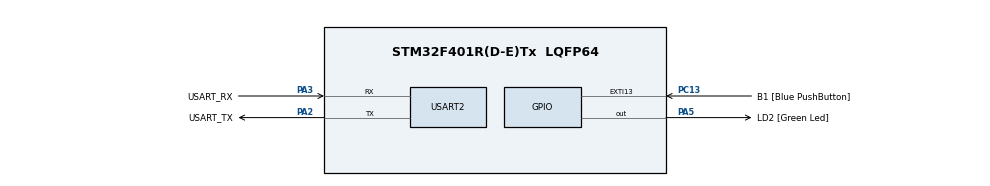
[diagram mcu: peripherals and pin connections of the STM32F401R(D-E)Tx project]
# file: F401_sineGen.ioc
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Mcu.Family=STM32F4
Mcu.Name=STM32F401R(D-E)Tx
Mcu.Package=LQFP64
NVIC.PriorityGroup=NVIC_PRIORITYGROUP_0
PA13.GPIO_Label=TMS
PA13.Mode=Serial_Wire
PA13.Signal=SYS_JTMS-SWDIO
PA14.GPIO_Label=TCK
PA14.Mode=Serial_Wire
PA14.Signal=SYS_JTCK-SWCLK
PA2.GPIO_Label=USART_TX
PA2.GPIO_Mode=GPIO_MODE_AF_PP
PA2.GPIO_PuPd=GPIO_NOPULL
PA2.GPIO_Speed=GPIO_SPEED_FREQ_LOW
PA2.Mode=Asynchronous
PA2.Signal=USART2_TX
PA3.GPIO_Label=USART_RX
PA3.GPIO_Mode=GPIO_MODE_AF_PP
PA3.GPIO_PuPd=GPIO_NOPULL
PA3.GPIO_Speed=GPIO_SPEED_FREQ_LOW
PA3.Mode=Asynchronous
PA3.Signal=USART2_RX
PA5.GPIO_Label=LD2 [Green Led]
PA5.GPIO_Mode=GPIO_MODE_OUTPUT_PP
PA5.GPIO_PuPd=GPIO_NOPULL
PA5.GPIO_Speed=GPIO_SPEED_FREQ_LOW
PA5.Signal=GPIO_Output
PB3.GPIO_Label=SWO
PB3.Signal=SYS_JTDO-SWO
PC13-ANTI_TAMP.GPIO_Label=B1 [Blue PushButton]
PC13-ANTI_TAMP.GPIO_ModeDefaultEXTI=GPIO_MODE_IT_FALLING
PC13-ANTI_TAMP.GPIO_PuPd=GPIO_NOPULL
PC13-ANTI_TAMP.Signal=GPXTI13
PC14-OSC32_IN.Mode=LSE-External-Oscillator
PC14-OSC32_IN.Signal=RCC_OSC32_IN
PC15-OSC32_OUT.Mode=LSE-External-Oscillator
PC15-OSC32_OUT.Signal=RCC_OSC32_OUT
PH0\ -\ OSC_IN.Mode=HSE-External-Clock-Source
PH0\ -\ OSC_IN.Signal=RCC_OSC_IN
PH1\ -\ OSC_OUT.Mode=HSE-External-Clock-Source
PH1\ -\ OSC_OUT.Signal=RCC_OSC_OUT
ProjectManager.HeapSize=0x200
ProjectManager.StackSize=0x400
ProjectManager.TargetToolchain=STM32CubeIDE
RCC.48MHZClocksFreq_Value=24000000
RCC.AHBFreq_Value=84000000
RCC.APB1CLKDivider=RCC_HCLK_DIV2
RCC.APB1Freq_Value=42000000
RCC.APB1TimFreq_Value=84000000
RCC.APB2Freq_Value=84000000
RCC.APB2TimFreq_Value=84000000
RCC.CortexFreq_Value=84000000
RCC.HCLKFreq_Value=84000000
RCC.HSE_VALUE=8000000
RCC.HSI_VALUE=16000000
RCC.PLLM=8
RCC.PLLN=84
RCC.PLLQ=7
RCC.SYSCLKFreq_VALUE=84000000
RCC.SYSCLKSource=RCC_SYSCLKSOURCE_PLLCLK
RCC.VCOOutputFreq_Value=168000000
STMicroelectronics.X-CUBE-AI.9.0.0.ActivationBufferSizeList=128
STMicroelectronics.X-CUBE-AI.9.0.0.ActivationBuffers=pool0
STMicroelectronics.X-CUBE-AI.9.0.0.ActivationNames=pool0
STMicroelectronics.X-CUBE-AI.9.0.0.ActivationSizes=AI_SINE_MODEL_DATA_ACTIVATION_1_SIZE
STMicroelectronics.X-CUBE-AI.9.0.0.HeapSize=0x800
STMicroelectronics.X-CUBE-AI.9.0.0.InternalRamActivationBufferMaxSize=AI_SINE_MODEL_DATA_ACTIVATIONS_SIZE
STMicroelectronics.X-CUBE-AI.9.0.0.LatestDirectoryUsed-be15a7543b8aec642143df37d2f76281d775ac8bf019addfea3917b66998c5c0=/home/stage002/Downloads
STMicroelectronics.X-CUBE-AI.9.0.0.MaximumNumberOfInputLayer=1
STMicroelectronics.X-CUBE-AI.9.0.0.MaximumNumberOfOutputLayer=1
STMicroelectronics.X-CUBE-AI.9.0.0.MaximumSizeOfInputLayer=1
STMicroelectronics.X-CUBE-AI.9.0.0.MaximumSizeOfOutputLayer=1
STMicroelectronics.X-CUBE-AI.9.0.0.ModelActualCompression-be15a7543b8aec642143df37d2f76281d775ac8bf019addfea3917b66998c5c0=0.0
STMicroelectronics.X-CUBE-AI.9.0.0.ModelCompression-be15a7543b8aec642143df37d2f76281d775ac8bf019addfea3917b66998c5c0=None
STMicroelectronics.X-CUBE-AI.9.0.0.ModelFlashOccupation-be15a7543b8aec642143df37d2f76281d775ac8bf019addfea3917b66998c5c0=1284
STMicroelectronics.X-CUBE-AI.9.0.0.ModelHashList=be15a7543b8aec642143df37d2f76281d775ac8bf019addfea3917b66998c5c0
STMicroelectronics.X-CUBE-AI.9.0.0.ModelKind-be15a7543b8aec642143df37d2f76281d775ac8bf019addfea3917b66998c5c0=TFLITE
STMicroelectronics.X-CUBE-AI.9.0.0.ModelMacc-be15a7543b8aec642143df37d2f76281d775ac8bf019addfea3917b66998c5c0=353
STMicroelectronics.X-CUBE-AI.9.0.0.ModelName-be15a7543b8aec642143df37d2f76281d775ac8bf019addfea3917b66998c5c0=sine_model
STMicroelectronics.X-CUBE-AI.9.0.0.ModelNameList=sine_model
STMicroelectronics.X-CUBE-AI.9.0.0.ModelRamOccupation-be15a7543b8aec642143df37d2f76281d775ac8bf019addfea3917b66998c5c0=128
STMicroelectronics.X-CUBE-AI.9.0.0.ModelStructureFile-be15a7543b8aec642143df37d2f76281d775ac8bf019addfea3917b66998c5c0=/home/stage002/Downloads/sine_model.tflite
STMicroelectronics.X-CUBE-AI.9.0.0.ModelType-be15a7543b8aec642143df37d2f76281d775ac8bf019addfea3917b66998c5c0=STM32Cube.AI MCU runtime
STMicroelectronics.X-CUBE-AI.9.0.0.ReadyForCodeGeneration=true
STMicroelectronics.X-CUBE-AI.9.0.0.StackSize=0x800
STMicroelectronics.X-CUBE-AI.9.0.0.WorkingBufferStartAddrList=0xFFFFFFFF
STMicroelectronics.X-CUBE-AI.9.0.0.XAaCUBEAaAICcArtificialOoIntelligenceJjCore=true
STMicroelectronics.X-CUBE-AI.9.0.0.copyWeightToRam-be15a7543b8aec642143df37d2f76281d775ac8bf019addfea3917b66998c5c0=false
STMicroelectronics.X-CUBE-AI.9.0.0.customLayerConfigEnabled-be15a7543b8aec642143df37d2f76281d775ac8bf019addfea3917b66998c5c0=false
STMicroelectronics.X-CUBE-AI.9.0.0.noOnnxIoTranspose-be15a7543b8aec642143df37d2f76281d775ac8bf019addfea3917b66998c5c0=false
STMicroelectronics.X-CUBE-AI.9.0.0.outputDirectory-be15a7543b8aec642143df37d2f76281d775ac8bf019addfea3917b66998c5c0=/home/stage002/.stm32cubemx/sine_model_output
STMicroelectronics.X-CUBE-AI.9.0.0.useInputAllocation-be15a7543b8aec642143df37d2f76281d775ac8bf019addfea3917b66998c5c0=true
STMicroelectronics.X-CUBE-AI.9.0.0.useOutputAllocation-be15a7543b8aec642143df37d2f76281d775ac8bf019addfea3917b66998c5c0=true
TIM10.Prescaler=80-1
USART2.VirtualMode=VM_ASYNC
VP_CRC_VS_CRC.Mode=CRC_Activate
VP_STMicroelectronics.X-CUBE-AI_VS_ArtificialOoIntelligenceJjXAaCUBEAaAI_9.0.0.Mode=ArtificialOoIntelligenceJjXAaCUBEAaAI
VP_TIM10_VS_ClockSourceINT.Mode=Enable_Timer
board=NUCLEO-F401RE

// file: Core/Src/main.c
/* USER CODE BEGIN Header */
/**
  ******************************************************************************
  * @file           : main.c
  * @brief          : Main program body
  ******************************************************************************
  * @attention
  *
  * Copyright (c) 2024 STMicroelectronics.
  * All rights reserved.
  *
  * This software is licensed under terms that can be found in the LICENSE file
  * in the root directory of this software component.
  * If no LICENSE file comes with this software, it is provided AS-IS.
  *
  ******************************************************************************
  */
/* USER CODE END Header */
#include "main.h"
#include <stdio.h>
#include "ai_datatypes_defines.h"
#include "ai_platform.h"
#include "sine_model.h"
#include "sine_model_data.h"

CRC_HandleTypeDef hcrc;

TIM_HandleTypeDef htim10;

UART_HandleTypeDef huart2;

static ai_buffer *ai_input;
static ai_buffer *ai_output;
char buf[50];
int buf_len = 0;
ai_error ai_err;
ai_i32 nbatch;
uint32_t timestamp;
float y_val;
ai_float input = 0;
ai_float a;

/* USER CODE BEGIN PFP */
void SystemClock_Config(void);
static void MX_GPIO_Init(void);
static void MX_USART2_UART_Init(void);
static void MX_TIM10_Init(void);
static void MX_CRC_Init(void);
/* USER CODE END PFP */

/* USER CODE BEGIN 0 */
// Chunk of memory used to hold intermediate values for neural network
  AI_ALIGNED(8) ai_u8 activations[AI_SINE_MODEL_DATA_ACTIVATIONS_SIZE];

  // Buffers used to store input and output tensors
  AI_ALIGNED(8) ai_i8 in_data[AI_SINE_MODEL_IN_1_SIZE_BYTES];
  AI_ALIGNED(8) ai_i8 out_data[AI_SINE_MODEL_OUT_1_SIZE_BYTES];
  // Pointer to our model
  ai_handle sine_model = AI_HANDLE_NULL;

/* USER CODE END 0 */
int aiInit(void) {

	/* Create and initialize the c-model */
	const ai_handle acts[] = {activations};

	ai_network_params ai_params = {
	    AI_SINE_MODEL_DATA_WEIGHTS(ai_sine_model_data_weights_get()),
	    AI_SINE_MODEL_DATA_ACTIVATIONS(activations)
	  };

	// Create instance of neural network
	ai_err = ai_sine_model_create(&sine_model, AI_SINE_MODEL_DATA_CONFIG);
	if (ai_err.type != AI_ERROR_NONE)
	  {
	    buf_len = sprintf(buf, "Error: could not create NN instance\r\n");
	    HAL_UART_Transmit(&huart2, (uint8_t *)buf, buf_len, 100);
	    while(1);
	  }
	// Initialize neural network
	if (!ai_sine_model_init(sine_model, &ai_params))
	  {
	    buf_len = sprintf(buf, "Error: could not initialize NN\r\n");
	    HAL_UART_Transmit(&huart2, (uint8_t *)buf, buf_len, 100);
	    while(1);
	  }

	/* Retrieve pointers to the model's input/output tensors */
	ai_input = ai_sine_model_inputs_get(sine_model, NULL);
	ai_output = ai_sine_model_outputs_get(sine_model, NULL);

	/* Set the @ of the input/output buffers when not allocated in the activations buffer */
	ai_input[0].data = AI_HANDLE_PTR(in_data);
	ai_output[0].data = AI_HANDLE_PTR(out_data);

#ifdef USE_AI_REPORT
  ai_network_get_report(network, &report);
#endif

	return 0;
}
int main(void)
{
  /* USER CODE BEGIN 1 */
  // Initialize wrapper structs that hold pointers to data and info about the
  // data (tensor height, width, channels)
  // Set working memory and get weights/biases from model
  // Set pointers wrapper structs to our data buffers

  ai_input[0].size = 1;
  ai_input[0].data = AI_HANDLE_PTR(in_data);
  ai_output[0].size = 1;
  ai_output[0].data = AI_HANDLE_PTR(out_data);

  /* USER CODE END 1 */

  /* MCU Configuration--------------------------------------------------------*/

  /* Reset of all peripherals, Initializes the Flash interface and the Systick. */
  HAL_Init();

  /* Configure the system clock */
  SystemClock_Config();

  /* Initialize all configured peripherals */
  MX_GPIO_Init();
  MX_USART2_UART_Init();
  MX_TIM10_Init();
  MX_CRC_Init();
  HAL_TIM_Base_Start(&htim10);
  printf(buf);
  printf(buf_len);
  // Greetings!
  buf_len = sprintf(buf, "\r\n\r\nSTM32 X-Cube-AI test\r\n");
  printf(buf_len);
  HAL_UART_Transmit(&huart2, (uint8_t *)buf, buf_len, 100);

  aiInit();

  /* Infinite loop */
  while (1)
  {
    // Fill input buffer (use test value)

      for (uint32_t i = 0; i < AI_SINE_MODEL_IN_1_SIZE; i++)
      {
        a = (input*3.14159265358979323846)/180;
	((ai_float *)in_data)[i] = a;
      }
      input++;

      // Get current timestamp
      timestamp = htim10.Instance->CNT;

      // Perform inference
      nbatch = ai_sine_model_run(sine_model, &ai_input[0], &ai_output[0]);
      if (nbatch != 1)
	{
	  buf_len = sprintf(buf, "Error: could not run inference\r\n");
	  HAL_UART_Transmit(&huart2, (uint8_t *)buf, buf_len, 100);
        }

      // Read output (predicted y) of neural network
      y_val = ((float *)out_data)[0];

        // Print output of neural network along with inference time (microseconds)
      buf_len = sprintf(buf,
                        "Input: %f | Output: %f | Duration: %lu\r\n",
			a,
			y_val,
			htim10.Instance->CNT - timestamp);
      HAL_UART_Transmit(&huart2, (uint8_t *)buf, buf_len, 100);

          // Wait before doing it again
      HAL_Delay(500);
  }
}
void SystemClock_Config(void)
{
  RCC_OscInitTypeDef RCC_OscInitStruct = {0};
  RCC_ClkInitTypeDef RCC_ClkInitStruct = {0};

  /** Configure the main internal regulator output voltage
  */
  __HAL_RCC_PWR_CLK_ENABLE();
  __HAL_PWR_VOLTAGESCALING_CONFIG(PWR_REGULATOR_VOLTAGE_SCALE2);

  /** Initializes the RCC Oscillators according to the specified parameters
  * in the RCC_OscInitTypeDef structure.
  */
  RCC_OscInitStruct.OscillatorType = RCC_OSCILLATORTYPE_HSI;
  RCC_OscInitStruct.HSIState = RCC_HSI_ON;
  RCC_OscInitStruct.HSICalibrationValue = RCC_HSICALIBRATION_DEFAULT;
  RCC_OscInitStruct.PLL.PLLState = RCC_PLL_ON;
  RCC_OscInitStruct.PLL.PLLSource = RCC_PLLSOURCE_HSI;
  RCC_OscInitStruct.PLL.PLLM = 8;
  RCC_OscInitStruct.PLL.PLLN = 80;
  RCC_OscInitStruct.PLL.PLLP = RCC_PLLP_DIV2;
  RCC_OscInitStruct.PLL.PLLQ = 7;
  if (HAL_RCC_OscConfig(&RCC_OscInitStruct) != HAL_OK)
  {
    Error_Handler();
  }

  /** Initializes the CPU, AHB and APB buses clocks
  */
  RCC_ClkInitStruct.ClockType = RCC_CLOCKTYPE_HCLK|RCC_CLOCKTYPE_SYSCLK
                              |RCC_CLOCKTYPE_PCLK1|RCC_CLOCKTYPE_PCLK2;
  RCC_ClkInitStruct.SYSCLKSource = RCC_SYSCLKSOURCE_PLLCLK;
  RCC_ClkInitStruct.AHBCLKDivider = RCC_SYSCLK_DIV1;
  RCC_ClkInitStruct.APB1CLKDivider = RCC_HCLK_DIV2;
  RCC_ClkInitStruct.APB2CLKDivider = RCC_HCLK_DIV1;

  if (HAL_RCC_ClockConfig(&RCC_ClkInitStruct, FLASH_LATENCY_2) != HAL_OK)
  {
    Error_Handler();
  }
}

static void MX_CRC_Init(void)
{

  hcrc.Instance = CRC;
  if (HAL_CRC_Init(&hcrc) != HAL_OK)
  {
    Error_Handler();
  }

}

static void MX_TIM10_Init(void)
{

  htim10.Instance = TIM10;
  htim10.Init.Prescaler = 80-1;
  htim10.Init.CounterMode = TIM_COUNTERMODE_UP;
  htim10.Init.Period = 65535;
  htim10.Init.ClockDivision = TIM_CLOCKDIVISION_DIV1;
  htim10.Init.AutoReloadPreload = TIM_AUTORELOAD_PRELOAD_DISABLE;
  if (HAL_TIM_Base_Init(&htim10) != HAL_OK)
  {
    Error_Handler();
  }

}

static void MX_USART2_UART_Init(void)
{

  huart2.Instance = USART2;
  huart2.Init.BaudRate = 115200;
  huart2.Init.WordLength = UART_WORDLENGTH_8B;
  huart2.Init.StopBits = UART_STOPBITS_1;
  huart2.Init.Parity = UART_PARITY_NONE;
  huart2.Init.Mode = UART_MODE_TX_RX;
  huart2.Init.HwFlowCtl = UART_HWCONTROL_NONE;
  huart2.Init.OverSampling = UART_OVERSAMPLING_16;
  if (HAL_UART_Init(&huart2) != HAL_OK)
  {
    Error_Handler();
  }

}

static void MX_GPIO_Init(void)
{
  GPIO_InitTypeDef GPIO_InitStruct = {0};

  /* GPIO Ports Clock Enable */
  __HAL_RCC_GPIOC_CLK_ENABLE();
  __HAL_RCC_GPIOH_CLK_ENABLE();
  __HAL_RCC_GPIOA_CLK_ENABLE();
  __HAL_RCC_GPIOB_CLK_ENABLE();

  /*Configure GPIO pin Output Level */
  HAL_GPIO_WritePin(LD2_GPIO_Port, LD2_Pin, GPIO_PIN_RESET);

  /*Configure GPIO pin : B1_Pin */
  GPIO_InitStruct.Pin = B1_Pin;
  GPIO_InitStruct.Mode = GPIO_MODE_IT_FALLING;
  GPIO_InitStruct.Pull = GPIO_NOPULL;
  HAL_GPIO_Init(B1_GPIO_Port, &GPIO_InitStruct);

  /*Configure GPIO pin : LD2_Pin */
  GPIO_InitStruct.Pin = LD2_Pin;
  GPIO_InitStruct.Mode = GPIO_MODE_OUTPUT_PP;
  GPIO_InitStruct.Pull = GPIO_NOPULL;
  GPIO_InitStruct.Speed = GPIO_SPEED_FREQ_LOW;
  HAL_GPIO_Init(LD2_GPIO_Port, &GPIO_InitStruct);

}

void Error_Handler(void)
{
  __disable_irq();
  while (1)
  {
  }
}
